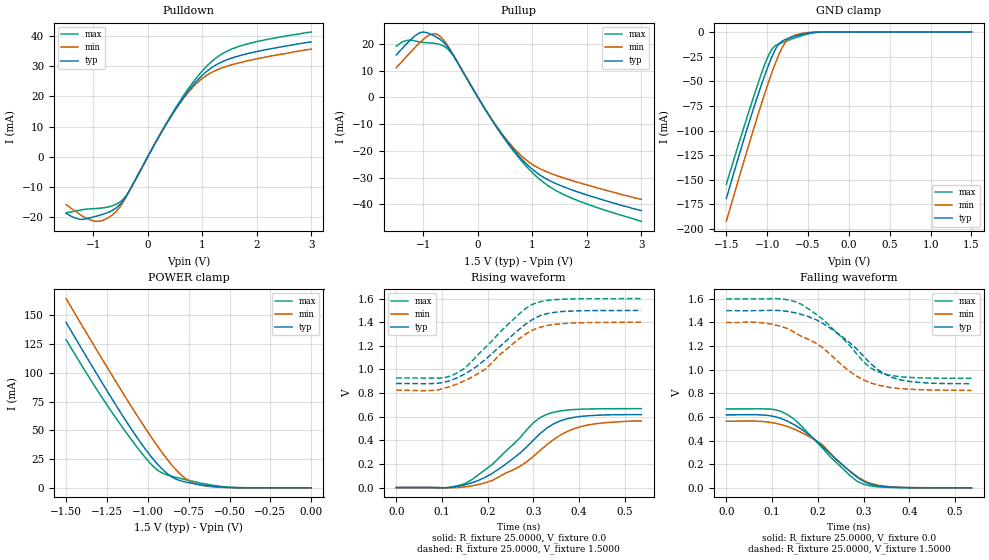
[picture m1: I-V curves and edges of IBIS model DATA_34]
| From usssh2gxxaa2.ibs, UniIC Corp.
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|When TDQS is enabled, NU_TDQS is a output with terminal resistance;
|When TDQS is disabled, NU_TDQS is a DM;
|   Model DATA_34
[Model]  DATA_34
Model_type I/O
Polarity   Non-Inverting
Enable   Active-High
Vinl =   0.61500000V
Vinh =   0.88500000V
Vmeas =   0.750000000V
Rref =   25.00000000
Vref =   0.75000000V
C_comp   1.6160pF   1.5840pF   1.6430pF
[Temperature Range]   25.0000   105.00   -40.0000
[Voltage Range]   1.5000V   1.4000V   1.6000V
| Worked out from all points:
|   slope of the pulldown table from 0 to 0.225 V, typ, clamps not added: 30.8 ohm
|   slope of the pullup table from 0 to 0.225 V, typ, clamps not added: 30.4 ohm
|   GND clamp passes 1 mA (typ) near -0.50 V on its own axis
|   POWER clamp passes 1 mA (typ) near -0.58 V on its own axis
|   rising waveform, R_fixture 25.0000, V_fixture 0.0: 20-80 % time 115ps typ, 127ps min, 108ps max; typ from 0 V to 0.618 V
|   rising waveform, R_fixture 25.0000, V_fixture 1.5000: 20-80 % time 113ps typ, 110ps min, 104ps max; typ from 0.881 V to 1.5 V
|   falling waveform, R_fixture 25.0000, V_fixture 0.0: 20-80 % time 110ps typ, 107ps min, 101ps max; typ from 0.618 V to 0 V
|   falling waveform, R_fixture 25.0000, V_fixture 1.5000: 20-80 % time 112ps typ, 124ps min, 104ps max; typ from 1.5 V to 0.882 V
[Pulldown]
|Voltage   I(typ)   I(min)   I(max)
-1.5V     -18.7mA    -15.9mA    -18.6mA
-1.25V    -20.76mA   -19.1mA    -17.76mA
-950mV    -19.72mA   -21.4mA    -17.18mA
-800mV    -18.94mA   -20.93mA   -16.9mA
-600mV    -17.23mA   -18.49mA   -15.92mA
-350mV    -11.62mA   -11.78mA   -11.64mA
200mV     6.523mA    6.541mA    6.641mA
550mV     16.83mA    16.7mA     17.3mA
900mV     25.12mA    24.36mA    26.27mA
1.25V     30.38mA    28.6mA     32.68mA
1.8V      34.01mA    31.64mA    37.23mA
3V        38mA       35.6mA     41.3mA
[Pullup]
|Voltage   I(typ)   I(min)   I(max)
-1.5V     15.8mA     11mA       19.1mA
-1.3V     20.21mA    15.5mA     21.26mA
-1.05V    24.23mA    20.76mA    20.6mA
-900mV    23.84mA    23.18mA    20.34mA
-750mV    22.38mA    23.55mA    20mA
-500mV    17.27mA    17.53mA    16.85mA
300mV     -9.744mA   -9.552mA   -9.868mA
600mV     -18.24mA   -17.62mA   -18.65mA
900mV     -25.07mA   -23.62mA   -26.06mA
1.2V      -29.82mA   -27.28mA   -31.71mA
1.55V     -33.24mA   -29.95mA   -36.08mA
3V        -42.3mA    -38.1mA    -46.3mA
[GND_clamp]
|Voltage   I(typ)   I(min)   I(max)
-1.5V     -169mA     -192.1mA   -154.5mA
-1.22V    -91.37mA   -113.1mA   -79.62mA
-1.06V    -51.03mA   -70.16mA   -39.64mA
-980mV    -32.74mA   -50.02mA   -22.86mA
-940mV    -24.55mA   -40.53mA   -17.05mA
-860mV    -12.39mA   -23.45mA   -12.14mA
-780mV    -7.577mA   -10.74mA   -9.536mA
-740mV    -6.329mA   -6.879mA   -8.307mA
-660mV    -4.221mA   -3.188mA   -5.953mA
-580mV    -2.407mA   -1.502mA   -3.789mA
-340mV    -36.93uA   -17.32uA   -106.5uA
1.5V      4.577nA    35.56nA    3.423nA
[POWER_clamp]
|Voltage   I(typ)   I(min)   I(max)
-1.5V     143.7mA    164.4mA    128.8mA
-1.26V    86.77mA    107.3mA    74.21mA
-1.12V    55.19mA    75.03mA    45.66mA
-1.02V    34.59mA    52.84mA    27.06mA
-940mV    20.5mA     36.08mA    15.4mA
-880mV    12.18mA    24.53mA    11.15mA
-840mV    8.415mA    17.64mA    9.537mA
-780mV    5.408mA    9.242mA    7.429mA
-700mV    3.206mA    3.136mA    4.858mA
-600mV    1.29mA     880.1uA    2.191mA
-440mV    104.5uA    76.21uA    176.8uA
0V        4.577nA    9.501nA    4.189nA
[Ramp]
| variable   typ   min   max
dV/dt_r  0.3707/0.1151n   0.3383/0.1299n   0.4011/0.1080n
dV/dt_f  0.3712/0.1121n   0.3450/0.1255n   0.4034/0.1038n
R_load = 25.0000
[Rising Waveform]
R_fixture= 25.0000
V_fixture= 0.0
V_fixture_min= 0.0
V_fixture_max= 0.0
|time   V(typ)   V(min)   V(max)
0s        0V         0V         0V
105ps     -1.852mV   -2.06mV    -1.884mV
150ps     23.49mV    6.451mV    33.6mV
195ps     87.14mV    41.76mV    152.4mV
255ps     244.2mV    148.6mV    362mV
300ps     402mV      264.9mV    549.6mV
330ps     505.8mV    365.4mV    621.6mV
360ps     566.8mV    446.9mV    649.5mV
405ps     603.3mV    517.9mV    663.9mV
536ps     617.9mV    563.8mV    668.5mV
[Rising Waveform]
R_fixture= 25.0000
V_fixture= 1.5000
V_fixture_min= 1.4000
V_fixture_max= 1.6000
|time   V(typ)   V(min)   V(max)
0s        881.4mV    825mV      927.8mV
90.91ps   883.4mV    825.3mV    926.9mV
135ps     932.4mV    879.9mV    974.6mV
150ps     961.6mV    905.4mV    1.012V
195ps     1.085V     1.003V     1.187V
270ps     1.343V     1.264V     1.474V
285ps     1.39V      1.305V     1.522V
315ps     1.456V     1.358V     1.574V
390ps     1.496V     1.394V     1.598V
536ps     1.5V       1.4V       1.6V
[Falling Waveform]
R_fixture= 25.0000
V_fixture= 0.0
V_fixture_min= 0.0
V_fixture_max= 0.0
|time   V(typ)   V(min)   V(max)
0s        617.9mV    563.8mV    668.5mV
105ps     604mV      548.3mV    663mV
135ps     561.8mV    517.6mV    617.1mV
165ps     494.7mV    466.8mV    520.5mV
210ps     350mV      365.5mV    337.5mV
240ps     243.9mV    238.7mV    215.6mV
270ps     140mV      142.7mV    105mV
300ps     55.27mV    62.93mV    30.7mV
360ps     5.644mV    8.856mV    3.014mV
536ps     0V         0V         0V
[Falling Waveform]
R_fixture= 25.0000
V_fixture= 1.5000
V_fixture_min= 1.4000
V_fixture_max= 1.6000
|time   V(typ)   V(min)   V(max)
0s        1.5V       1.4V       1.6V
105ps     1.503V     1.381V     1.602V
135ps     1.493V     1.347V     1.591V
165ps     1.467V     1.28V      1.552V
210ps     1.395V     1.188V     1.43V
240ps     1.317V     1.084V     1.318V
300ps     1.115V     913.2mV    1.067V
345ps     965.9mV    858.2mV    964.2mV
405ps     898.3mV    834mV      933.8mV
536ps     881.5mV    825mV      927.7mV
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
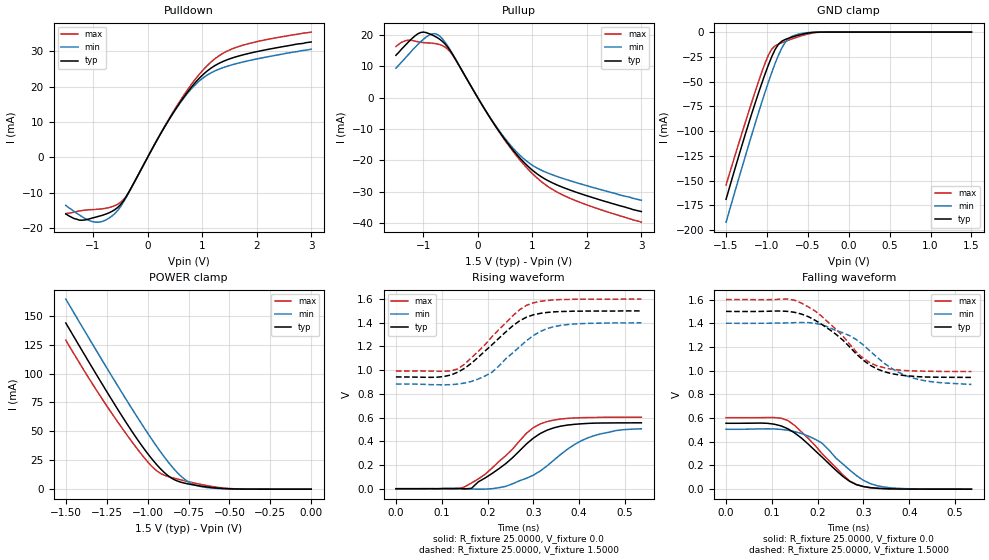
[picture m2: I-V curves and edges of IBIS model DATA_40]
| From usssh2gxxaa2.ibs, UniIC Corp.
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|   Model DATA_40
[Model]  DATA_40
Model_type I/O
Polarity   Non-Inverting
Enable   Active-High
Vinl =   0.61500000V
Vinh =   0.88500000V
Vmeas =   0.750000000V
Rref =   25.00000000
Vref =   0.75000000V
C_comp   1.6160pF   1.5840pF   1.6430pF
[Temperature Range]   25.0000   105.00   -40.0000
[Voltage Range]   1.5000V   1.4000V   1.6000V
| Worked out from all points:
|   slope of the pulldown table from 0 to 0.225 V, typ, clamps not added: 35.8 ohm
|   slope of the pullup table from 0 to 0.225 V, typ, clamps not added: 35.3 ohm
|   GND clamp passes 1 mA (typ) near -0.50 V on its own axis
|   POWER clamp passes 1 mA (typ) near -0.58 V on its own axis
|   rising waveform, R_fixture 25.0000, V_fixture 0.0: 20-80 % time 104ps typ, 112ps min, 95.2ps max; typ from 0 V to 0.556 V
|   rising waveform, R_fixture 25.0000, V_fixture 1.5000: 20-80 % time 96.8ps typ, 91ps min, 93.6ps max; typ from 0.943 V to 1.5 V
|   falling waveform, R_fixture 25.0000, V_fixture 0.0: 20-80 % time 94.1ps typ, 87.6ps min, 90.3ps max; typ from 0.556 V to 0 V
|   falling waveform, R_fixture 25.0000, V_fixture 1.5000: 20-80 % time 102ps typ, 107ps min, 94.3ps max; typ from 1.5 V to 0.943 V
[Pulldown]
|Voltage   I(typ)   I(min)   I(max)
-1.5V     -16mA      -13.6mA    -15.9mA
-1.25V    -17.76mA   -16.3mA    -15.16mA
-950mV    -16.91mA   -18.34mA   -14.72mA
-800mV    -16.23mA   -17.95mA   -14.49mA
-600mV    -14.78mA   -15.88mA   -13.66mA
-350mV    -9.992mA   -10.13mA   -10mA
200mV     5.609mA    5.624mA    5.711mA
600mV     15.61mA    15.45mA    16.08mA
950mV     22.39mA    21.62mA    23.51mA
1.25V     26.07mA    24.54mA    28.05mA
1.75V     28.97mA    26.96mA    31.71mA
3V        32.6mA     30.6mA     35.4mA
[Pullup]
|Voltage   I(typ)   I(min)   I(max)
-1.5V     13.5mA     9.4mA      16.3mA
-1.3V     17.21mA    13.2mA     18.26mA
-1.05V    20.75mA    17.76mA    17.66mA
-850mV    20.09mA    20.25mA    17.38mA
-750mV    19.21mA    20.21mA    17.15mA
-500mV    14.86mA    15.07mA    14.48mA
300mV     -8.378mA   -8.211mA   -8.485mA
600mV     -15.67mA   -15.14mA   -16.03mA
900mV     -21.53mA   -20.28mA   -22.38mA
1.2V      -25.59mA   -23.41mA   -27.23mA
1.6V      -28.86mA   -25.97mA   -31.37mA
3V        -36.3mA    -32.7mA    -39.7mA
[GND_clamp]
|Voltage   I(typ)   I(min)   I(max)
-1.5V     -169mA     -192.1mA   -154.5mA
-1.22V    -91.37mA   -113.1mA   -79.62mA
-1.06V    -51.03mA   -70.16mA   -39.64mA
-980mV    -32.74mA   -50.02mA   -22.86mA
-940mV    -24.55mA   -40.53mA   -17.05mA
-860mV    -12.39mA   -23.45mA   -12.14mA
-780mV    -7.577mA   -10.74mA   -9.536mA
-740mV    -6.329mA   -6.879mA   -8.307mA
-660mV    -4.221mA   -3.188mA   -5.953mA
-580mV    -2.407mA   -1.502mA   -3.789mA
-340mV    -36.93uA   -17.32uA   -106.5uA
1.5V      4.577nA    35.56nA    3.423nA
[POWER_clamp]
|Voltage   I(typ)   I(min)   I(max)
-1.5V     143.7mA    164.4mA    128.8mA
-1.26V    86.77mA    107.3mA    74.21mA
-1.12V    55.19mA    75.03mA    45.66mA
-1.02V    34.59mA    52.84mA    27.06mA
-940mV    20.5mA     36.08mA    15.4mA
-880mV    12.18mA    24.53mA    11.15mA
-840mV    8.415mA    17.64mA    9.537mA
-780mV    5.408mA    9.242mA    7.429mA
-700mV    3.206mA    3.136mA    4.858mA
-600mV    1.29mA     880.1uA    2.191mA
-440mV    104.5uA    76.21uA    176.8uA
0V        4.577nA    9.501nA    4.189nA
[Ramp]
| variable   typ   min   max
dV/dt_r  0.3336/0.1041n   0.3032/0.1121n   0.3619/95.2449p
dV/dt_f  0.3342/0.1019n   0.3101/0.1074n   0.3642/94.3055p
R_load = 25.0000
[Rising Waveform]
R_fixture= 25.0000
V_fixture= 0.0
V_fixture_min= 0.0
V_fixture_max= 0.0
|time   V(typ)   V(min)   V(max)
0s        0V         0V         0V
135ps     3.196mV    5.234uV    -2.501mV
165ps     3.18mV     -2.889mV   48.34mV
240ps     212.1mV    20.21mV    279.3mV
285ps     377.3mV    87.7mV     467.4mV
330ps     493.7mV    192.5mV    566.4mV
375ps     537.1mV    334.2mV    593.5mV
420ps     551.2mV    430.4mV    600.5mV
480ps     555.3mV    490.1mV    602.7mV
536ps     556mV      505.3mV    603.1mV
[Rising Waveform]
R_fixture= 25.0000
V_fixture= 1.5000
V_fixture_min= 1.4000
V_fixture_max= 1.6000
|time   V(typ)   V(min)   V(max)
0s        943.1mV    883.2mV    993mV
90.91ps   941.1mV    877mV      991.1mV
135ps     982.9mV    882.5mV    1.01V
165ps     1.059V     905.4mV    1.106V
210ps     1.215V     982.9mV    1.283V
270ps     1.416V     1.197V     1.51V
300ps     1.467V     1.292V     1.568V
330ps     1.487V     1.351V     1.588V
375ps     1.496V     1.385V     1.597V
536ps     1.5V       1.4V       1.6V
[Falling Waveform]
R_fixture= 25.0000
V_fixture= 0.0
V_fixture_min= 0.0
V_fixture_max= 0.0
|time   V(typ)   V(min)   V(max)
0s        556mV      505.2mV    603.1mV
90.91ps   555.5mV    509.1mV    604.3mV
135ps     509.5mV    497.1mV    579.2mV
180ps     378.3mV    447.8mV    426.9mV
210ps     269.6mV    387.1mV    298.6mV
255ps     107.9mV    212.5mV    120.8mV
285ps     37.64mV    114mV      38.33mV
315ps     12.97mV    46.79mV    12.04mV
345ps     4.435mV    18.08mV    4.247mV
536ps     0V         0V         0V
[Falling Waveform]
R_fixture= 25.0000
V_fixture= 1.5000
V_fixture_min= 1.4000
V_fixture_max= 1.6000
|time   V(typ)   V(min)   V(max)
0s        1.5V       1.4V       1.6V
150ps     1.492V     1.405V     1.594V
210ps     1.388V     1.387V     1.455V
255ps     1.258V     1.32V      1.293V
285ps     1.139V     1.261V     1.156V
330ps     1.014V     1.112V     1.04V
360ps     976.2mV    1.023V     1.013V
405ps     953.6mV    941.3mV    998.7mV
450ps     945.3mV    905.9mV    994.5mV
536ps     943.1mV    883.5mV    993mV
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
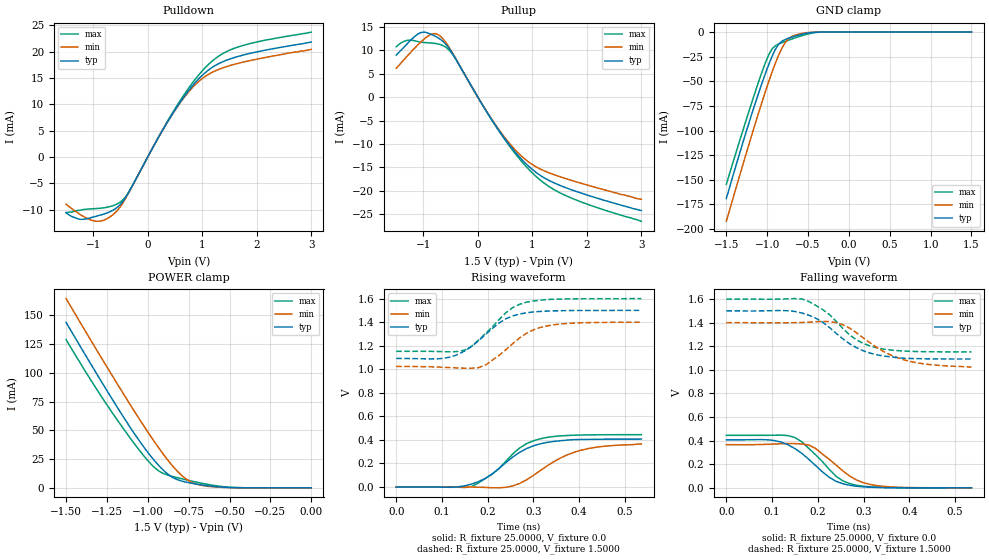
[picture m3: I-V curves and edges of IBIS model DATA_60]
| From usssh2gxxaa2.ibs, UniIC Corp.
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|   Model DATA_60
[Model]  DATA_60
Model_type I/O
Polarity   Non-Inverting
Enable   Active-High
Vinl =   0.61500000V
Vinh =   0.88500000V
Vmeas =   0.750000000V
Rref =   25.00000000
Vref =   0.75000000V
C_comp   1.6160pF   1.5840pF   1.6430pF
[Temperature Range]   25.0000   105.00   -40.0000
[Voltage Range]   1.5000V   1.4000V   1.6000V
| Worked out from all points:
|   slope of the pulldown table from 0 to 0.225 V, typ, clamps not added: 53.4 ohm
|   slope of the pullup table from 0 to 0.225 V, typ, clamps not added: 52.6 ohm
|   GND clamp passes 1 mA (typ) near -0.50 V on its own axis
|   POWER clamp passes 1 mA (typ) near -0.58 V on its own axis
|   rising waveform, R_fixture 25.0000, V_fixture 0.0: 20-80 % time 86.5ps typ, 97.6ps min, 78.4ps max; typ from 0 V to 0.407 V
|   rising waveform, R_fixture 25.0000, V_fixture 1.5000: 20-80 % time 78.8ps typ, 76.6ps min, 72.1ps max; typ from 1.09 V to 1.5 V
|   falling waveform, R_fixture 25.0000, V_fixture 0.0: 20-80 % time 75.8ps typ, 73.7ps min, 68.8ps max; typ from 0.407 V to 0 V
|   falling waveform, R_fixture 25.0000, V_fixture 1.5000: 20-80 % time 88.4ps typ, 96.6ps min, 79.8ps max; typ from 1.5 V to 1.09 V
[Pulldown]
|Voltage   I(typ)   I(min)   I(max)
-1.5V     -10.6mA    -9mA       -10.6mA
-1.25V    -11.86mA   -10.9mA    -10.13mA
-1V       -11.42mA   -12.13mA   -9.85mA
-800mV    -10.84mA   -11.99mA   -9.67mA
-600mV    -9.882mA   -10.62mA   -9.123mA
-350mV    -6.704mA   -6.798mA   -6.711mA
200mV     3.763mA    3.773mA    3.832mA
600mV     10.46mA    10.35mA    10.78mA
950mV     14.98mA    14.46mA    15.74mA
1.25V     17.42mA    16.38mA    18.75mA
1.75V     19.33mA    17.99mA    21.16mA
3V        21.8mA     20.4mA     23.7mA
[Pullup]
|Voltage   I(typ)   I(min)   I(max)
-1.5V     9mA        6.2mA      10.8mA
-1.3V     11.41mA    8.8mA      12.16mA
-1.05V    13.82mA    11.79mA    11.78mA
-850mV    13.42mA    13.49mA    11.59mA
-750mV    12.84mA    13.5mA     11.44mA
-600mV    11.47mA    11.88mA    10.78mA
-450mV    9.041mA    9.128mA    8.905mA
300mV     -5.62mA    -5.507mA   -5.692mA
850mV     -13.84mA   -13.09mA   -14.35mA
1.2V      -17.1mA    -15.63mA   -18.21mA
1.55V     -19.04mA   -17.15mA   -20.68mA
3V        -24.2mA    -21.8mA    -26.5mA
[GND_clamp]
|Voltage   I(typ)   I(min)   I(max)
-1.5V     -169mA     -192.1mA   -154.5mA
-1.22V    -91.37mA   -113.1mA   -79.62mA
-1.06V    -51.03mA   -70.16mA   -39.64mA
-980mV    -32.74mA   -50.02mA   -22.86mA
-940mV    -24.55mA   -40.53mA   -17.05mA
-860mV    -12.39mA   -23.45mA   -12.14mA
-780mV    -7.577mA   -10.74mA   -9.536mA
-740mV    -6.329mA   -6.879mA   -8.307mA
-660mV    -4.221mA   -3.188mA   -5.953mA
-580mV    -2.407mA   -1.502mA   -3.789mA
-340mV    -36.93uA   -17.32uA   -106.5uA
1.5V      4.577nA    35.56nA    3.423nA
[POWER_clamp]
|Voltage   I(typ)   I(min)   I(max)
-1.5V     143.7mA    164.4mA    128.8mA
-1.26V    86.77mA    107.3mA    74.21mA
-1.12V    55.19mA    75.03mA    45.66mA
-1.02V    34.59mA    52.84mA    27.06mA
-940mV    20.5mA     36.08mA    15.4mA
-880mV    12.18mA    24.53mA    11.15mA
-840mV    8.415mA    17.64mA    9.537mA
-780mV    5.408mA    9.242mA    7.429mA
-700mV    3.206mA    3.136mA    4.858mA
-600mV    1.29mA     880.1uA    2.191mA
-440mV    104.5uA    76.21uA    176.8uA
0V        4.577nA    9.501nA    4.189nA
[Ramp]
| variable   typ   min   max
dV/dt_r  0.2442/86.5366p   0.2195/97.6806p   0.2669/78.4595p
dV/dt_f  0.2448/88.3671p   0.2262/97.1921p   0.2688/79.7930p
R_load = 25.0000
[Rising Waveform]
R_fixture= 25.0000
V_fixture= 0.0
V_fixture_min= 0.0
V_fixture_max= 0.0
|time   V(typ)   V(min)   V(max)
0s        0V         0V         0V
120ps     -2.381mV   651.1uV    -193.2uV
165ps     25.57mV    -238.8uV   4.749mV
195ps     73.7mV     -3.251mV   72.87mV
240ps     208.5mV    -2.203mV   219.9mV
285ps     326.4mV    61.3mV     368.3mV
330ps     379.2mV    179.7mV    421.7mV
360ps     393.6mV    248.2mV    434.5mV
405ps     403.9mV    313.5mV    441.7mV
536ps     407mV      365.8mV    444.8mV
[Rising Waveform]
R_fixture= 25.0000
V_fixture= 1.5000
V_fixture_min= 1.4000
V_fixture_max= 1.6000
|time   V(typ)   V(min)   V(max)
0s        1.092V     1.024V     1.152V
105ps     1.094V     1.016V     1.149V
150ps     1.156V     1.009V     1.163V
165ps     1.195V     1.009V     1.195V
195ps     1.294V     1.035V     1.303V
240ps     1.429V     1.167V     1.481V
285ps     1.48V      1.306V     1.57V
315ps     1.491V     1.355V     1.587V
360ps     1.497V     1.385V     1.596V
536ps     1.5V       1.4V       1.6V
[Falling Waveform]
R_fixture= 25.0000
V_fixture= 0.0
V_fixture_min= 0.0
V_fixture_max= 0.0
|time   V(typ)   V(min)   V(max)
0s        407mV      365.9mV    444.9mV
105ps     400.8mV    371.4mV    446.1mV
150ps     332.6mV    375.1mV    426.3mV
180ps     242.9mV    363mV      335.1mV
225ps     89.18mV    242.1mV    156.7mV
255ps     34.49mV    142.9mV    58.62mV
285ps     13.4mV     65.65mV    21.44mV
315ps     5.146mV    28.04mV    8.508mV
360ps     1.268mV    7.753mV    1.932mV
536ps     0V         0V         0V
[Falling Waveform]
R_fixture= 25.0000
V_fixture= 1.5000
V_fixture_min= 1.4000
V_fixture_max= 1.6000
|time   V(typ)   V(min)   V(max)
0s        1.5V       1.4V       1.6V
120ps     1.503V     1.399V     1.6V
165ps     1.482V     1.402V     1.601V
210ps     1.406V     1.411V     1.513V
240ps     1.31V      1.401V     1.412V
285ps     1.187V     1.313V     1.253V
330ps     1.127V     1.187V     1.186V
360ps     1.11V      1.125V     1.168V
405ps     1.096V     1.069V     1.157V
536ps     1.092V     1.024V     1.152V
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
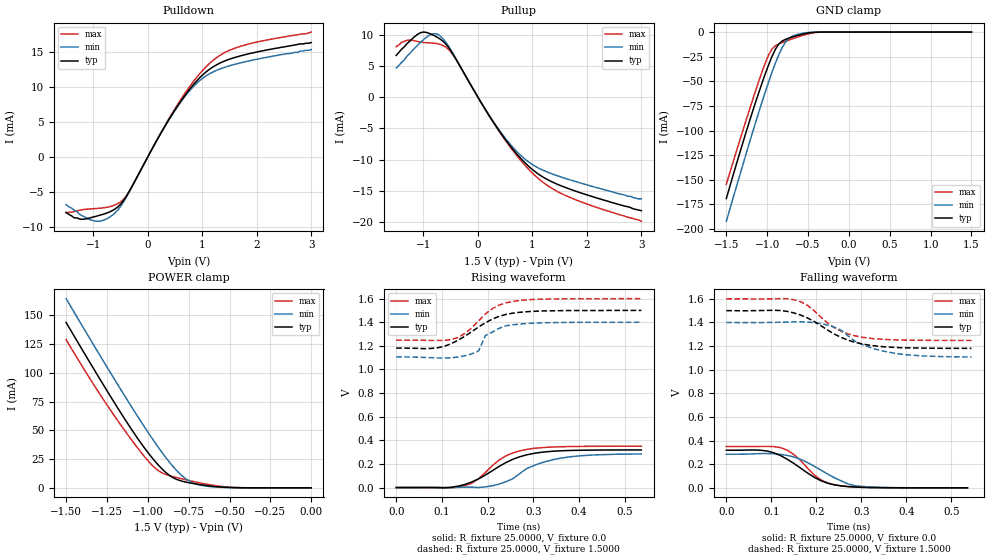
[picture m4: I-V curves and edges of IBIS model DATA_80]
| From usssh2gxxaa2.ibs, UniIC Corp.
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|   Model DATA_80
[Model]  DATA_80
Model_type I/O
Polarity   Non-Inverting
Enable   Active-High
Vinl =   0.61500000V
Vinh =   0.88500000V
Vmeas =   0.750000000V
Rref =   25.00000000
Vref =   0.75000000V
C_comp   1.6160pF   1.5840pF   1.6430pF
[Temperature Range]   25.0000   105.00   -40.0000
[Voltage Range]   1.5000V   1.4000V   1.6000V
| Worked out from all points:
|   slope of the pulldown table from 0 to 0.225 V, typ, clamps not added: 70.9 ohm
|   slope of the pullup table from 0 to 0.225 V, typ, clamps not added: 70 ohm
|   GND clamp passes 1 mA (typ) near -0.50 V on its own axis
|   POWER clamp passes 1 mA (typ) near -0.58 V on its own axis
|   rising waveform, R_fixture 25.0000, V_fixture 0.0: 20-80 % time 91.4ps typ, 89.9ps min, 68.8ps max; typ from 0 V to 0.318 V
|   rising waveform, R_fixture 25.0000, V_fixture 1.5000: 20-80 % time 82.5ps typ, 40.7ps min, 63ps max; typ from 1.18 V to 1.5 V
|   falling waveform, R_fixture 25.0000, V_fixture 0.0: 20-80 % time 79.1ps typ, 83.6ps min, 58.6ps max; typ from 0.318 V to 0 V
|   falling waveform, R_fixture 25.0000, V_fixture 1.5000: 20-80 % time 93.8ps typ, 88.6ps min, 74.8ps max; typ from 1.5 V to 1.18 V
[Pulldown]
|Voltage   I(typ)   I(min)   I(max)
-1.5V     -7.9mA     -6.8mA     -8mA
-1.25V    -8.86mA    -8.2mA     -7.6mA
-950mV    -8.47mA    -9.17mA    -7.36mA
-750mV    -8mA       -8.822mA   -7.188mA
-600mV    -7.422mA   -7.983mA   -6.843mA
-350mV    -5.045mA   -5.116mA   -5.049mA
200mV     2.832mA    2.839mA    2.884mA
600mV     7.865mA    7.781mA    8.105mA
950mV     11.26mA    10.86mA    11.83mA
1.25V     13.07mA    12.3mA     14.08mA
1.8V      14.6mA     13.58mA    15.99mA
3V        16.3mA     15.3mA     17.8mA
[Pullup]
|Voltage   I(typ)   I(min)   I(max)
-1.5V     6.7mA      4.7mA      8.1mA
-1.3V     8.61mA     6.6mA      9.12mA
-1.05V    10.35mA    8.83mA     8.84mA
-750mV    9.639mA    10.14mA    8.588mA
-600mV    8.621mA    8.936mA    8.099mA
-450mV    6.804mA    6.87mA     6.7mA
300mV     -4.228mA   -4.143mA   -4.283mA
600mV     -7.898mA   -7.622mA   -8.083mA
900mV     -10.83mA   -10.19mA   -11.27mA
1.25V     -13.09mA   -11.92mA   -14mA
1.6V      -14.46mA   -13.01mA   -15.73mA
3V        -18.2mA    -16.3mA    -19.9mA
[GND_clamp]
|Voltage   I(typ)   I(min)   I(max)
-1.5V     -169mA     -192.1mA   -154.5mA
-1.22V    -91.37mA   -113.1mA   -79.62mA
-1.06V    -51.03mA   -70.16mA   -39.64mA
-980mV    -32.74mA   -50.02mA   -22.86mA
-940mV    -24.55mA   -40.53mA   -17.05mA
-860mV    -12.39mA   -23.45mA   -12.14mA
-780mV    -7.577mA   -10.74mA   -9.536mA
-740mV    -6.329mA   -6.879mA   -8.307mA
-660mV    -4.221mA   -3.188mA   -5.953mA
-580mV    -2.407mA   -1.502mA   -3.789mA
-340mV    -36.93uA   -17.32uA   -106.5uA
1.5V      4.577nA    35.56nA    3.423nA
[POWER_clamp]
|Voltage   I(typ)   I(min)   I(max)
-1.5V     143.7mA    164.4mA    128.8mA
-1.26V    86.77mA    107.3mA    74.21mA
-1.12V    55.19mA    75.03mA    45.66mA
-1.02V    34.59mA    52.84mA    27.06mA
-940mV    20.5mA     36.08mA    15.4mA
-880mV    12.18mA    24.53mA    11.15mA
-840mV    8.415mA    17.64mA    9.537mA
-780mV    5.408mA    9.242mA    7.429mA
-700mV    3.206mA    3.136mA    4.858mA
-600mV    1.29mA     880.1uA    2.191mA
-440mV    104.5uA    76.21uA    176.8uA
0V        4.577nA    9.501nA    4.189nA
[Ramp]
| variable   typ   min   max
dV/dt_r  0.1912/91.4560p   0.1708/0.1049n   0.2099/68.8004p
dV/dt_f  0.1914/93.7667p   0.1764/0.1049n   0.2112/74.8340p
R_load = 25.0000
[Rising Waveform]
R_fixture= 25.0000
V_fixture= 0.0
V_fixture_min= 0.0
V_fixture_max= 0.0
|time   V(typ)   V(min)   V(max)
0s        0V         0V         0V
105ps     -2.434mV   279.1uV    -600.2uV
150ps     25.97mV    3.738mV    16.58mV
180ps     73.35mV    124uV      74.68mV
225ps     178.9mV    29.24mV    233mV
255ps     239.2mV    74.7mV     292.8mV
285ps     276.7mV    160.2mV    322.6mV
330ps     303.6mV    223.6mV    341.1mV
375ps     313.4mV    257.7mV    346.9mV
536ps     318.5mV    284.6mV    349.9mV
[Rising Waveform]
R_fixture= 25.0000
V_fixture= 1.5000
V_fixture_min= 1.4000
V_fixture_max= 1.6000
|time   V(typ)   V(min)   V(max)
0s        1.181V     1.107V     1.248V
90.91ps   1.184V     1.097V     1.246V
135ps     1.247V     1.105V     1.271V
180ps     1.359V     1.157V     1.411V
195ps     1.396V     1.287V     1.47V
210ps     1.426V     1.316V     1.515V
240ps     1.466V     1.37V      1.564V
255ps     1.477V     1.378V     1.576V
315ps     1.495V     1.394V     1.595V
536ps     1.5V       1.4V       1.6V
[Falling Waveform]
R_fixture= 25.0000
V_fixture= 0.0
V_fixture_min= 0.0
V_fixture_max= 0.0
|time   V(typ)   V(min)   V(max)
0s        318.5mV    284.3mV    349.9mV
75.76ps   318.4mV    290.3mV    350.6mV
120ps     274mV      283.8mV    340.8mV
150ps     207.1mV    261.2mV    282.5mV
195ps     90.47mV    183.9mV    109.9mV
210ps     60.43mV    150.7mV    68.31mV
240ps     25.28mV    85.76mV    26.77mV
270ps     10.66mV    33.93mV    10.99mV
300ps     4.654mV    12.32mV    4.529mV
536ps     0V         0V         0V
[Falling Waveform]
R_fixture= 25.0000
V_fixture= 1.5000
V_fixture_min= 1.4000
V_fixture_max= 1.6000
|time   V(typ)   V(min)   V(max)
0s        1.5V       1.4V       1.6V
120ps     1.501V     1.402V     1.602V
165ps     1.463V     1.406V     1.576V
180ps     1.439V     1.404V     1.546V
240ps     1.302V     1.36V      1.356V
270ps     1.251V     1.288V     1.304V
300ps     1.22V      1.217V     1.276V
345ps     1.196V     1.161V     1.258V
390ps     1.186V     1.131V     1.251V
545ps     1.181V     1.108V     1.248V
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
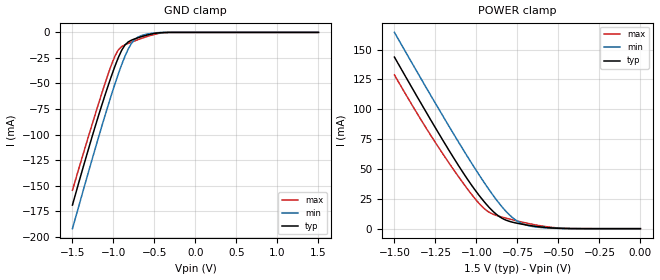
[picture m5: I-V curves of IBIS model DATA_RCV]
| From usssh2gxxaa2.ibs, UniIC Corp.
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|   Model DATA_RCV
[Model]  DATA_RCV
Model_type Input
Polarity   Non-Inverting
Vinl =   0.60000000V
Vinh =   0.90000000V
C_comp   1.6160pF   1.5840pF   1.6430pF
[Temperature Range]   25.0000   105.00   -40.0000
[Voltage Range]   1.5000V   1.4000V   1.6000V
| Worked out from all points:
|   GND clamp passes 1 mA (typ) near -0.50 V on its own axis
|   POWER clamp passes 1 mA (typ) near -0.58 V on its own axis
[GND_clamp]
|Voltage   I(typ)   I(min)   I(max)
-1.5V     -169mA     -192.1mA   -154.5mA
-1.22V    -91.37mA   -113.1mA   -79.62mA
-1.06V    -51.03mA   -70.16mA   -39.64mA
-980mV    -32.74mA   -50.02mA   -22.86mA
-940mV    -24.55mA   -40.53mA   -17.05mA
-860mV    -12.39mA   -23.45mA   -12.14mA
-780mV    -7.577mA   -10.74mA   -9.536mA
-740mV    -6.329mA   -6.879mA   -8.307mA
-660mV    -4.221mA   -3.188mA   -5.953mA
-580mV    -2.407mA   -1.502mA   -3.789mA
-340mV    -36.93uA   -17.32uA   -106.5uA
1.5V      4.577nA    35.56nA    3.423nA
[POWER_clamp]
|Voltage   I(typ)   I(min)   I(max)
-1.5V     143.7mA    164.4mA    128.8mA
-1.26V    86.77mA    107.3mA    74.21mA
-1.12V    55.19mA    75.03mA    45.66mA
-1.02V    34.59mA    52.84mA    27.06mA
-940mV    20.5mA     36.08mA    15.4mA
-880mV    12.18mA    24.53mA    11.15mA
-840mV    8.415mA    17.64mA    9.537mA
-780mV    5.408mA    9.242mA    7.429mA
-700mV    3.206mA    3.136mA    4.858mA
-600mV    1.29mA     880.1uA    2.191mA
-440mV    104.5uA    76.21uA    176.8uA
0V        4.577nA    9.501nA    4.189nA
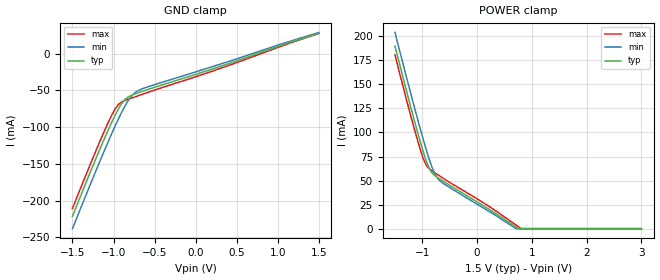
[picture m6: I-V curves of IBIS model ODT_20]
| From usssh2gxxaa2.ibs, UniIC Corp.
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|   Model ODT_20
[Model]  ODT_20
Model_type Input
Polarity   Non-Inverting
Vinl =   0.60000000V
Vinh =   0.90000000V
C_comp   1.6160pF   1.5840pF   1.6430pF
[Temperature Range]   25.0000   105.00   -40.0000
[Voltage Range]   1.5000V   1.4000V   1.6000V
[GND_clamp]
|Voltage   I(typ)   I(min)   I(max)
-1.5V     -221.3mA   -238mA     -210.6mA
-1.14V    -123mA     -139.3mA   -112.4mA
-1.06V    -102.6mA   -118.4mA   -92.41mA
-980mV    -83.58mA   -98.21mA   -75.13mA
-940mV    -75.02mA   -88.61mA   -69.07mA
-860mV    -62.11mA   -71.04mA   -63.61mA
-780mV    -56.5mA    -57.51mA   -60.4mA
-740mV    -54.81mA   -53.14mA   -58.83mA
-660mV    -51.71mA   -48.23mA   -55.7mA
-540mV    -47.2mA    -43.57mA   -51.04mA
260mV     -18.77mA   -15.68mA   -21.57mA
1.5V      27.81mA    28.87mA    27.4mA
[POWER_clamp]
|Voltage   I(typ)   I(min)   I(max)
-1.5V     189.9mA    204.1mA    180.8mA
-1.18V    119.6mA    133.7mA    110.6mA
-1.06V    94.72mA    108.3mA    86.52mA
-980mV    79.37mA    92.09mA    72.48mA
-920mV    69.16mA    80.49mA    65.23mA
-840mV    59.32mA    66.47mA    60.92mA
-760mV    54.75mA    55.71mA    57.74mA
-720mV    53.13mA    52.21mA    56.19mA
-660mV    50.83mA    48.85mA    53.89mA
200mV     20.8mA     18.58mA    23.8mA
749.7mV   0A         NA         NA
3V        0A         0A         0A
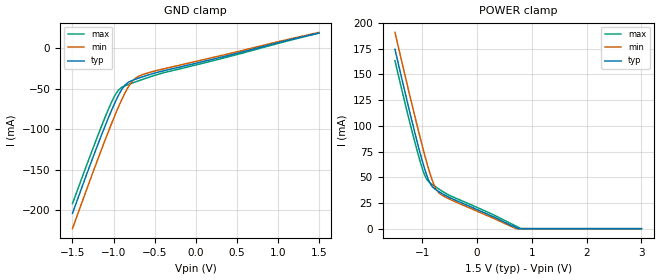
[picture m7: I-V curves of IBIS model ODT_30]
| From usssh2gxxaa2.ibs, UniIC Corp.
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|   Model ODT_30
[Model]  ODT_30
Model_type Input
Polarity   Non-Inverting
Vinl =   0.60000000V
Vinh =   0.90000000V
C_comp   1.6160pF   1.5840pF   1.6430pF
[Temperature Range]   25.0000   105.00   -40.0000
[Voltage Range]   1.5000V   1.4000V   1.6000V
[GND_clamp]
|Voltage   I(typ)   I(min)   I(max)
-1.5V     -203.9mA   -222.7mA   -191.9mA
-1.18V    -116mA     -134mA     -105mA
-1.06V    -85.46mA   -102.3mA   -74.85mA
-980mV    -66.67mA   -82.16mA   -57.74mA
-940mV    -58.23mA   -72.6mA    -51.76mA
-900mV    -50.99mA   -63.55mA   -48.39mA
-860mV    -45.58mA   -55.21mA   -46.49mA
-780mV    -40.23mA   -41.96mA   -43.48mA
-740mV    -38.69mA   -37.77mA   -42.03mA
-660mV    -35.93mA   -33.27mA   -39.16mA
-460mV    -29.78mA   -27.31mA   -32.47mA
1.5V      18.56mA    19.28mA    18.29mA
[POWER_clamp]
|Voltage   I(typ)   I(min)   I(max)
-1.5V     174.4mA    190.9mA    163.4mA
-1.2V     106.8mA    123.1mA    97.13mA
-1.06V    77.31mA    92.72mA    69.11mA
-980mV    62.01mA    76.14mA    55.2mA
-920mV    51.96mA    64.34mA    48.02mA
-840mV    42.39mA    50.19mA    43.81mA
-760mV    38.13mA    39.56mA    40.77mA
-680mV    35.36mA    34.07mA    37.89mA
-420mV    28.27mA    26.72mA    30.33mA
300mV     11.49mA    10.07mA    13.42mA
749.7mV   0A         NA         NA
3V        0A         0A         0A
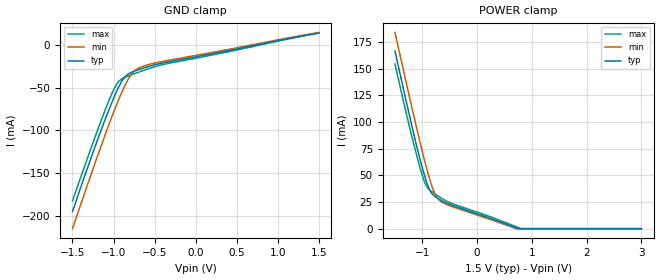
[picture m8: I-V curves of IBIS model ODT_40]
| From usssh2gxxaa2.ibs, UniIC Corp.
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|   Model ODT_40
[Model]  ODT_40
Model_type Input
Polarity   Non-Inverting
Vinl =   0.60000000V
Vinh =   0.90000000V
C_comp   1.6160pF   1.5840pF   1.6430pF
[Temperature Range]   25.0000   105.00   -40.0000
[Voltage Range]   1.5000V   1.4000V   1.6000V
[GND_clamp]
|Voltage   I(typ)   I(min)   I(max)
-1.5V     -195.1mA   -215.1mA   -182.6mA
-1.34V    -150.3mA   -170.1mA   -138.7mA
-1.14V    -96.9mA    -115.3mA   -85.81mA
-1.06V    -76.87mA   -94.26mA   -66.06mA
-980mV    -58.2mA    -74.13mA   -49.03mA
-940mV    -49.83mA   -64.59mA   -43.1mA
-860mV    -37.29mA   -47.28mA   -37.92mA
-780mV    -32.08mA   -34.17mA   -35.01mA
-740mV    -30.62mA   -30.06mA   -33.61mA
-660mV    -28.02mA   -25.77mA   -30.87mA
-460mV    -22.5mA    -20.58mA   -24.67mA
1.5V      13.93mA    14.47mA    13.72mA
[POWER_clamp]
|Voltage   I(typ)   I(min)   I(max)
-1.5V     166.7mA    184.2mA    154.7mA
-1.32V    125.3mA    142.8mA    113.9mA
-1.2V     98.37mA    115.6mA    88.28mA
-1.06V    68.61mA    84.93mA    60.4mA
-980mV    53.32mA    68.17mA    46.55mA
-920mV    43.34mA    56.28mA    39.41mA
-840mV    33.91mA    42.05mA    35.25mA
-760mV    29.81mA    31.47mA    32.28mA
-680mV    27.23mA    26.18mA    29.5mA
-460mV    21.99mA    20.82mA    23.56mA
749.7mV   0A         NA         NA
3V        0A         0A         0A
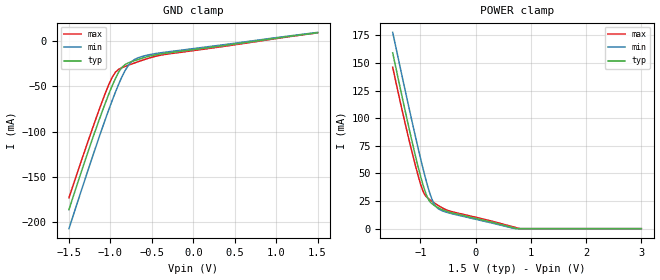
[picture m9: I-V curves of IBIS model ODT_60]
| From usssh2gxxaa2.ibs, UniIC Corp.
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|   Model ODT_60
[Model]  ODT_60
Model_type Input
Polarity   Non-Inverting
Vinl =   0.60000000V
Vinh =   0.90000000V
C_comp   1.6160pF   1.5840pF   1.6430pF
[Temperature Range]   25.0000   105.00   -40.0000
[Voltage Range]   1.5000V   1.4000V   1.6000V
[GND_clamp]
|Voltage   I(typ)   I(min)   I(max)
-1.5V     -186.4mA   -207.4mA   -173.2mA
-1.3V     -130.5mA   -151.1mA   -118.8mA
-1.14V    -88.18mA   -107.3mA   -76.93mA
-1.06V    -68.27mA   -86.23mA   -57.26mA
-980mV    -49.72mA   -66.1mA    -40.32mA
-940mV    -41.41mA   -56.58mA   -34.42mA
-860mV    -29mA      -39.34mA   -29.33mA
-780mV    -23.92mA   -26.37mA   -26.53mA
-740mV    -22.53mA   -22.35mA   -25.19mA
-660mV    -20.1mA    -18.26mA   -22.58mA
-460mV    -15.2mA    -13.82mA   -16.86mA
1.5V      9.293mA    9.657mA    9.152mA
[POWER_clamp]
|Voltage   I(typ)   I(min)   I(max)
-1.5V     159mA      177.6mA    146.1mA
-1.36V    126.3mA    144.9mA    113.9mA
-1.22V    94.37mA    112.7mA    83.57mA
-1.08V    64mA       81.49mA    55.47mA
-980mV    44.62mA    60.21mA    37.89mA
-920mV    34.72mA    48.21mA    30.79mA
-840mV    25.42mA    33.91mA    26.68mA
-760mV    21.47mA    23.37mA    23.78mA
-680mV    19.09mA    18.27mA    21.09mA
-460mV    14.73mA    13.93mA    15.81mA
749.7mV   0A         NA         NA
3V        0A         0A         0A
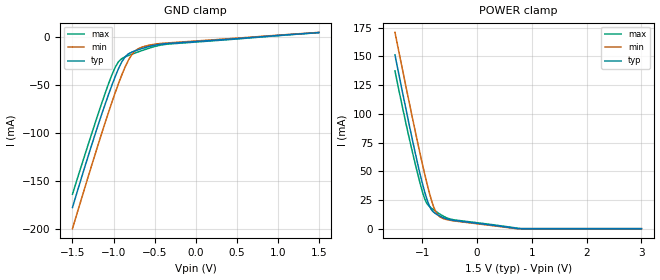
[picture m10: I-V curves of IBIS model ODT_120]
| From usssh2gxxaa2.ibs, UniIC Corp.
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|   Model ODT_120
[Model]  ODT_120
Model_type Input
Polarity   Non-Inverting
Vinl =   0.60000000V
Vinh =   0.90000000V
C_comp   1.6160pF   1.5840pF   1.6430pF
[Temperature Range]   25.0000   105.00   -40.0000
[Voltage Range]   1.5000V   1.4000V   1.6000V
[GND_clamp]
|Voltage   I(typ)   I(min)   I(max)
-1.5V     -177.7mA   -199.8mA   -163.9mA
-1.3V     -121.7mA   -143.2mA   -109.7mA
-1.14V    -79.45mA   -99.31mA   -68.04mA
-1.06V    -59.66mA   -78.19mA   -48.46mA
-980mV    -41.23mA   -58.06mA   -31.59mA
-940mV    -32.98mA   -48.56mA   -25.74mA
-860mV    -20.7mA    -31.4mA    -20.74mA
-780mV    -15.76mA   -18.56mA   -18.04mA
-740mV    -14.44mA   -14.62mA   -16.75mA
-580mV    -10.15mA   -8.797mA   -11.95mA
-340mV    -6.759mA   -6.155mA   -7.411mA
1.5V      4.649mA    4.833mA    4.578mA
[POWER_clamp]
|Voltage   I(typ)   I(min)   I(max)
-1.5V     151.4mA    171mA      137.4mA
-1.34V    113.6mA    133.2mA    100.6mA
-1.22V    85.96mA    105.4mA    74.69mA
-1.08V    55.33mA    73.76mA    46.73mA
-980mV    35.92mA    52.26mA    29.24mA
-920mV    26.09mA    40.16mA    22.17mA
-840mV    16.92mA    25.78mA    18.11mA
-760mV    13.13mA    15.26mA    15.27mA
-680mV    10.93mA    10.35mA    12.68mA
-440mV    7.293mA    6.886mA    7.861mA
749.8mV   0A         NA         NA
3V        0A         0A         0A
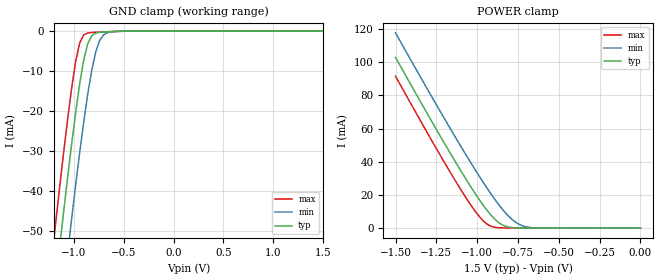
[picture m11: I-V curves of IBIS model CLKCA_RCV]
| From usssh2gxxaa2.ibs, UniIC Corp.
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|   Model CLKCA_RCV
[Model]  CLKCA_RCV
Model_type Input
Polarity   Non-Inverting
Vinl =   0.60000000V
Vinh =   0.90000000V
C_comp   0.8363pF   0.8073pF   0.8594pF
[Temperature Range]   25.0000   105.00   -40.0000
[Voltage Range]   1.5000V   1.4000V   1.6000V
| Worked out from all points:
|   GND clamp passes 1 mA (typ) near -0.81 V on its own axis
|   POWER clamp passes 1 mA (typ) near -0.82 V on its own axis
[GND_clamp]
|Voltage   I(typ)   I(min)   I(max)
-1.5V     -137.6mA   -156.9mA   -122.8mA
-1.22V    -71.72mA   -91.13mA   -56.7mA
-1.18V    -62.6mA    -81.98mA   -47.6mA
-1.14V    -53.62mA   -72.92mA   -38.67mA
-1.1V     -44.81mA   -63.99mA   -30mA
-1.02V    -27.95mA   -46.6mA    -14.01mA
-940mV    -13.07mA   -30.21mA   -2.891mA
-900mV    -7.188mA   -22.64mA   -945.6uA
-860mV    -3.14mA    -15.73mA   -470.6uA
-780mV    -507.6uA   -5.214mA   -295uA
-660mV    -182.5uA   -381.8uA   -158.1uA
1.5V      428.1pA    539.3pA    376.4pA
[POWER_clamp]
|Voltage   I(typ)   I(min)   I(max)
-1.5V     102.9mA    117.7mA    91.58mA
-1.18V    47.75mA    62.6mA     36.22mA
-1.08V    31.38mA    46.06mA    20.1mA
-1V       19.09mA    33.31mA    8.645mA
-940mV    10.82mA    24.21mA    2.495mA
-920mV    8.387mA    21.31mA    1.356mA
-880mV    4.308mA    15.78mA    379.7uA
-840mV    1.685mA    10.76mA    168.9uA
-780mV    312.9uA    4.737mA    93.35uA
-720mV    93.05uA    1.366mA    52.82uA
-660mV    42.22uA    282.5uA    24.02uA
0V        428.1pA    340.7pA    534pA
